VERSION 5.7 ;
BUSBITCHARS "[]" ;
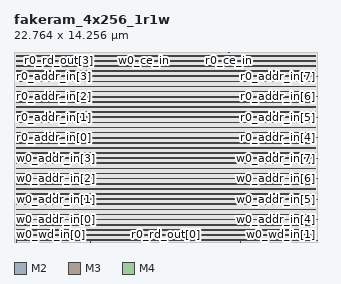
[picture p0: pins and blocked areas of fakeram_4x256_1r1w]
MACRO fakeram_4x256_1r1w
  FOREIGN fakeram_4x256_1r1w 0 0 ;
  SYMMETRY X Y R90 ;
  SIZE 22.764 BY 14.256 ;
  CLASS BLOCK ;
  PIN w0_wd_in[0]
    DIRECTION INPUT ;
    USE SIGNAL ;
    SHAPE ABUTMENT ;
    PORT
      LAYER M2 ;
      RECT 0.000 0.138 0.036 0.150 ;
    END
  END w0_wd_in[0]
  PIN w0_wd_in[1]
    DIRECTION INPUT ;
    USE SIGNAL ;
    SHAPE ABUTMENT ;
    PORT
      LAYER M2 ;
      RECT 22.728 0.138 22.764 0.150 ;
    END
  END w0_wd_in[1]
  PIN w0_wd_in[2]
    DIRECTION INPUT ;
    USE SIGNAL ;
    SHAPE ABUTMENT ;
    PORT
      LAYER M3 ;
      RECT 0.161 0.000 0.175 0.042 ;
    END
  END w0_wd_in[2]
  PIN w0_wd_in[3]
    DIRECTION INPUT ;
    USE SIGNAL ;
    SHAPE ABUTMENT ;
    PORT
      LAYER M3 ;
      RECT 5.761 0.000 5.775 0.042 ;
    END
  END w0_wd_in[3]
  PIN r0_rd_out[0]
    DIRECTION OUTPUT ;
    USE SIGNAL ;
    SHAPE ABUTMENT ;
    PORT
      LAYER M3 ;
      RECT 11.361 0.000 11.375 0.042 ;
    END
  END r0_rd_out[0]
  PIN r0_rd_out[1]
    DIRECTION OUTPUT ;
    USE SIGNAL ;
    SHAPE ABUTMENT ;
    PORT
      LAYER M3 ;
      RECT 16.961 0.000 16.975 0.042 ;
    END
  END r0_rd_out[1]
  PIN r0_rd_out[2]
    DIRECTION OUTPUT ;
    USE SIGNAL ;
    SHAPE ABUTMENT ;
    PORT
      LAYER M3 ;
      RECT 0.161 14.214 0.175 14.256 ;
    END
  END r0_rd_out[2]
  PIN r0_rd_out[3]
    DIRECTION OUTPUT ;
    USE SIGNAL ;
    SHAPE ABUTMENT ;
    PORT
      LAYER M3 ;
      RECT 3.353 14.214 3.367 14.256 ;
    END
  END r0_rd_out[3]
  PIN w0_addr_in[0]
    DIRECTION INPUT ;
    USE SIGNAL ;
    SHAPE ABUTMENT ;
    PORT
      LAYER M2 ;
      RECT 0.000 1.674 0.036 1.686 ;
    END
  END w0_addr_in[0]
  PIN w0_addr_in[1]
    DIRECTION INPUT ;
    USE SIGNAL ;
    SHAPE ABUTMENT ;
    PORT
      LAYER M2 ;
      RECT 0.000 3.210 0.036 3.222 ;
    END
  END w0_addr_in[1]
  PIN w0_addr_in[2]
    DIRECTION INPUT ;
    USE SIGNAL ;
    SHAPE ABUTMENT ;
    PORT
      LAYER M2 ;
      RECT 0.000 4.746 0.036 4.758 ;
    END
  END w0_addr_in[2]
  PIN w0_addr_in[3]
    DIRECTION INPUT ;
    USE SIGNAL ;
    SHAPE ABUTMENT ;
    PORT
      LAYER M2 ;
      RECT 0.000 6.282 0.036 6.294 ;
    END
  END w0_addr_in[3]
  PIN w0_addr_in[4]
    DIRECTION INPUT ;
    USE SIGNAL ;
    SHAPE ABUTMENT ;
    PORT
      LAYER M2 ;
      RECT 22.728 1.674 22.764 1.686 ;
    END
  END w0_addr_in[4]
  PIN w0_addr_in[5]
    DIRECTION INPUT ;
    USE SIGNAL ;
    SHAPE ABUTMENT ;
    PORT
      LAYER M2 ;
      RECT 22.728 3.210 22.764 3.222 ;
    END
  END w0_addr_in[5]
  PIN w0_addr_in[6]
    DIRECTION INPUT ;
    USE SIGNAL ;
    SHAPE ABUTMENT ;
    PORT
      LAYER M2 ;
      RECT 22.728 4.746 22.764 4.758 ;
    END
  END w0_addr_in[6]
  PIN w0_addr_in[7]
    DIRECTION INPUT ;
    USE SIGNAL ;
    SHAPE ABUTMENT ;
    PORT
      LAYER M2 ;
      RECT 22.728 6.282 22.764 6.294 ;
    END
  END w0_addr_in[7]
  PIN r0_addr_in[0]
    DIRECTION INPUT ;
    USE SIGNAL ;
    SHAPE ABUTMENT ;
    PORT
      LAYER M2 ;
      RECT 0.000 7.818 0.036 7.830 ;
    END
  END r0_addr_in[0]
  PIN r0_addr_in[1]
    DIRECTION INPUT ;
    USE SIGNAL ;
    SHAPE ABUTMENT ;
    PORT
      LAYER M2 ;
      RECT 0.000 9.354 0.036 9.366 ;
    END
  END r0_addr_in[1]
  PIN r0_addr_in[2]
    DIRECTION INPUT ;
    USE SIGNAL ;
    SHAPE ABUTMENT ;
    PORT
      LAYER M2 ;
      RECT 0.000 10.890 0.036 10.902 ;
    END
  END r0_addr_in[2]
  PIN r0_addr_in[3]
    DIRECTION INPUT ;
    USE SIGNAL ;
    SHAPE ABUTMENT ;
    PORT
      LAYER M2 ;
      RECT 0.000 12.426 0.036 12.438 ;
    END
  END r0_addr_in[3]
  PIN r0_addr_in[4]
    DIRECTION INPUT ;
    USE SIGNAL ;
    SHAPE ABUTMENT ;
    PORT
      LAYER M2 ;
      RECT 22.728 7.818 22.764 7.830 ;
    END
  END r0_addr_in[4]
  PIN r0_addr_in[5]
    DIRECTION INPUT ;
    USE SIGNAL ;
    SHAPE ABUTMENT ;
    PORT
      LAYER M2 ;
      RECT 22.728 9.354 22.764 9.366 ;
    END
  END r0_addr_in[5]
  PIN r0_addr_in[6]
    DIRECTION INPUT ;
    USE SIGNAL ;
    SHAPE ABUTMENT ;
    PORT
      LAYER M2 ;
      RECT 22.728 10.890 22.764 10.902 ;
    END
  END r0_addr_in[6]
  PIN r0_addr_in[7]
    DIRECTION INPUT ;
    USE SIGNAL ;
    SHAPE ABUTMENT ;
    PORT
      LAYER M2 ;
      RECT 22.728 12.426 22.764 12.438 ;
    END
  END r0_addr_in[7]
  PIN w0_we_in
    DIRECTION INPUT ;
    USE SIGNAL ;
    SHAPE ABUTMENT ;
    PORT
      LAYER M3 ;
      RECT 6.545 14.214 6.559 14.256 ;
    END
  END w0_we_in
  PIN w0_ce_in
    DIRECTION INPUT ;
    USE SIGNAL ;
    SHAPE ABUTMENT ;
    PORT
      LAYER M3 ;
      RECT 9.737 14.214 9.751 14.256 ;
    END
  END w0_ce_in
  PIN w0_clk
    DIRECTION INPUT ;
    USE SIGNAL ;
    SHAPE ABUTMENT ;
    PORT
      LAYER M3 ;
      RECT 12.929 14.214 12.943 14.256 ;
    END
  END w0_clk
  PIN r0_ce_in
    DIRECTION INPUT ;
    USE SIGNAL ;
    SHAPE ABUTMENT ;
    PORT
      LAYER M3 ;
      RECT 16.121 14.214 16.135 14.256 ;
    END
  END r0_ce_in
  PIN r0_clk
    DIRECTION INPUT ;
    USE SIGNAL ;
    SHAPE ABUTMENT ;
    PORT
      LAYER M3 ;
      RECT 19.313 14.214 19.327 14.256 ;
    END
  END r0_clk
  PIN VSS
    DIRECTION INOUT ;
    USE GROUND ;
    PORT
      LAYER M4 ;
      RECT 0.168 0.120 22.596 0.168 ;
      RECT 0.168 0.504 22.596 0.552 ;
      RECT 0.168 0.888 22.596 0.936 ;
      RECT 0.168 1.272 22.596 1.320 ;
      RECT 0.168 1.656 22.596 1.704 ;
      RECT 0.168 2.040 22.596 2.088 ;
      RECT 0.168 2.424 22.596 2.472 ;
      RECT 0.168 2.808 22.596 2.856 ;
      RECT 0.168 3.192 22.596 3.240 ;
      RECT 0.168 3.576 22.596 3.624 ;
      RECT 0.168 3.960 22.596 4.008 ;
      RECT 0.168 4.344 22.596 4.392 ;
      RECT 0.168 4.728 22.596 4.776 ;
      RECT 0.168 5.112 22.596 5.160 ;
      RECT 0.168 5.496 22.596 5.544 ;
      RECT 0.168 5.880 22.596 5.928 ;
      RECT 0.168 6.264 22.596 6.312 ;
      RECT 0.168 6.648 22.596 6.696 ;
      RECT 0.168 7.032 22.596 7.080 ;
      RECT 0.168 7.416 22.596 7.464 ;
      RECT 0.168 7.800 22.596 7.848 ;
      RECT 0.168 8.184 22.596 8.232 ;
      RECT 0.168 8.568 22.596 8.616 ;
      RECT 0.168 8.952 22.596 9.000 ;
      RECT 0.168 9.336 22.596 9.384 ;
      RECT 0.168 9.720 22.596 9.768 ;
      RECT 0.168 10.104 22.596 10.152 ;
      RECT 0.168 10.488 22.596 10.536 ;
      RECT 0.168 10.872 22.596 10.920 ;
      RECT 0.168 11.256 22.596 11.304 ;
      RECT 0.168 11.640 22.596 11.688 ;
      RECT 0.168 12.024 22.596 12.072 ;
      RECT 0.168 12.408 22.596 12.456 ;
      RECT 0.168 12.792 22.596 12.840 ;
      RECT 0.168 13.176 22.596 13.224 ;
      RECT 0.168 13.560 22.596 13.608 ;
      RECT 0.168 13.944 22.596 13.992 ;
    END
  END VSS
  PIN VDD
    DIRECTION INOUT ;
    USE POWER ;
    PORT
      LAYER M4 ;
      RECT 0.168 0.120 22.596 0.168 ;
      RECT 0.168 0.504 22.596 0.552 ;
      RECT 0.168 0.888 22.596 0.936 ;
      RECT 0.168 1.272 22.596 1.320 ;
      RECT 0.168 1.656 22.596 1.704 ;
      RECT 0.168 2.040 22.596 2.088 ;
      RECT 0.168 2.424 22.596 2.472 ;
      RECT 0.168 2.808 22.596 2.856 ;
      RECT 0.168 3.192 22.596 3.240 ;
      RECT 0.168 3.576 22.596 3.624 ;
      RECT 0.168 3.960 22.596 4.008 ;
      RECT 0.168 4.344 22.596 4.392 ;
      RECT 0.168 4.728 22.596 4.776 ;
      RECT 0.168 5.112 22.596 5.160 ;
      RECT 0.168 5.496 22.596 5.544 ;
      RECT 0.168 5.880 22.596 5.928 ;
      RECT 0.168 6.264 22.596 6.312 ;
      RECT 0.168 6.648 22.596 6.696 ;
      RECT 0.168 7.032 22.596 7.080 ;
      RECT 0.168 7.416 22.596 7.464 ;
      RECT 0.168 7.800 22.596 7.848 ;
      RECT 0.168 8.184 22.596 8.232 ;
      RECT 0.168 8.568 22.596 8.616 ;
      RECT 0.168 8.952 22.596 9.000 ;
      RECT 0.168 9.336 22.596 9.384 ;
      RECT 0.168 9.720 22.596 9.768 ;
      RECT 0.168 10.104 22.596 10.152 ;
      RECT 0.168 10.488 22.596 10.536 ;
      RECT 0.168 10.872 22.596 10.920 ;
      RECT 0.168 11.256 22.596 11.304 ;
      RECT 0.168 11.640 22.596 11.688 ;
      RECT 0.168 12.024 22.596 12.072 ;
      RECT 0.168 12.408 22.596 12.456 ;
      RECT 0.168 12.792 22.596 12.840 ;
      RECT 0.168 13.176 22.596 13.224 ;
      RECT 0.168 13.560 22.596 13.608 ;
      RECT 0.168 13.944 22.596 13.992 ;
    END
  END VDD
  OBS
    LAYER M1 ;
    RECT 0 0 22.764 14.256 ;
    LAYER M2 ;
    RECT 0 0 22.764 14.256 ;
    LAYER M3 ;
    RECT 0 0 22.764 14.256 ;
    LAYER M4 ;
    RECT 0 0 22.764 14.256 ;
  END
END fakeram_4x256_1r1w

END LIBRARY
